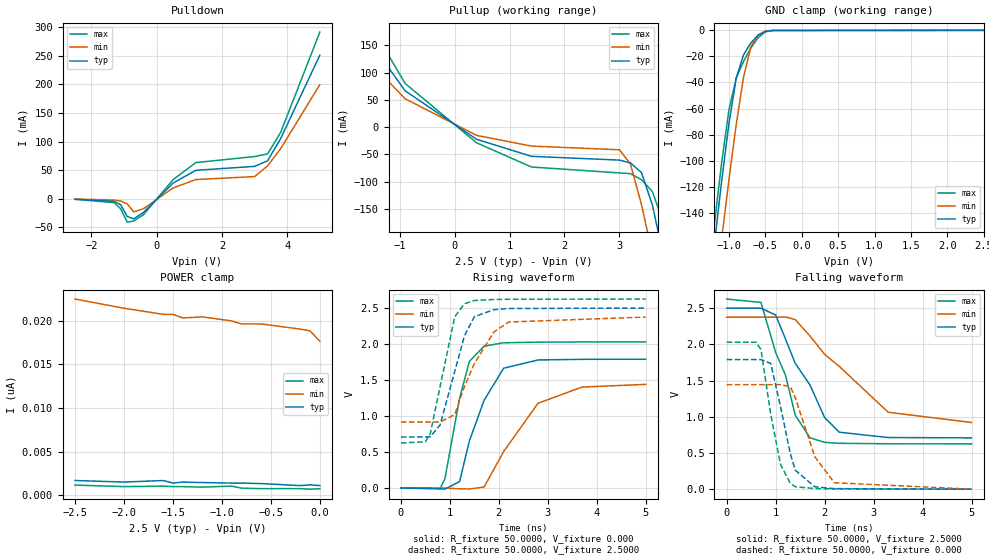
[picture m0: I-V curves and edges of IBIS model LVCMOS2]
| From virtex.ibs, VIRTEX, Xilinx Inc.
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| Note -  the values for Vref specified below refer to the IBIS
| Vref (the voltage  to which the load resistor is connected in
| the IBIS model) and not the Vref of the corresponding
| differential input standard.
| These 2 Vrefs will not necessarily have the same value for a given
| standard.
|   Model LVCMOS2
[Model]   LVCMOS2
Model_type   I/O
Polarity   Non-Inverting
Enable   Active-Low
Vinl =   0.800V
Vinh =   1.700V
Vmeas =   1.2500V
Cref =  35.0000pF
Rref =   1.0000M
Vref =  0.000V
C_comp   6.5000pF   5.0000pF   8.0000pF
[Temperature Range]   27.0000   100.0000   0.000
[Voltage Range]   2.5000V   2.3750V   2.6250V
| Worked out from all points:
|   slope of the pulldown table from 0 to 0.375 V, typ, clamps not added: 17.7 ohm
|   slope of the pullup table from 0 to 0.375 V, typ, clamps not added: 17.9 ohm
|   GND clamp passes 1 mA (typ) near -0.51 V on its own axis
|   rising waveform, R_fixture 50.0000, V_fixture 0.000: 20-80 % time 525ps typ, 808ps min, 368ps max; typ from 0 V to 1.79 V
|   rising waveform, R_fixture 50.0000, V_fixture 2.5000: 20-80 % time 456ps typ, 605ps min, 355ps max; typ from 0.708 V to 2.5 V
|   falling waveform, R_fixture 50.0000, V_fixture 2.5000: 20-80 % time 769ps typ, 1.22ns min, 524ps max; typ from 2.5 V to 0.709 V
|   falling waveform, R_fixture 50.0000, V_fixture 0.000: 20-80 % time 338ps typ, 465ps min, 296ps max; typ from 1.79 V to 0.001 V
[Pulldown]
| voltage   I(typ)   I(min)   I(max)
-2.5V     -900uA     -600uA     -1.1mA
-1.3V     -4.8mA     -2.4mA     -6.9mA
-1.1V     -10.5mA    -4mA       -17.7mA
-900mV    -31.17mA   -9.17mA    -41.13mA
-700mV    -35.25mA   -23.08mA   -39.09mA
-400mV    -23.96mA   -17.41mA   -27.92mA
500mV     27.16mA    18.74mA    33.11mA
1.2V      49.71mA    33.52mA    63.24mA
3V        56.55mA    38.7mA     73.81mA
3.4V      66.37mA    57.4mA     78.39mA
3.8V      105.3mA    87.69mA    116.1mA
5V        251.3mA    199.7mA    291.7mA
[Pullup]
| voltage   I(typ)   I(min)   I(max)
-2.5V     294mA      224.6mA    353.6mA
-1.9V     207.9mA    157.1mA    251.6mA
-900mV    66.61mA    52.06mA    80.14mA
400mV     -22.23mA   -15.11mA   -28.69mA
1.4V      -53.52mA   -34.76mA   -73.1mA
3V        -60.44mA   -41.5mA    -83.95mA
3.2V      -65.62mA   -67.47mA   -85.26mA
3.4V      -83.06mA   -141.8mA   -96.26mA
3.6V      -142.9mA   -233.3mA   -118.3mA
3.8V      -236.6mA   -330.2mA   -175.6mA
4V        -338.4mA   -429.6mA   -269.9mA
5V        -873.3mA   -939.1mA   -808.1mA
[GND_clamp]
| voltage   I(typ)   I(min)   I(max)
-2.5V     -852.1mA   -861.3mA   -847.6mA
-1.2V     -163.3mA   -206.7mA   -148.3mA
-1.1V     -115.2mA   -159.6mA   -101mA
-1V       -71.03mA   -114.2mA   -60.76mA
-900mV    -36.42mA   -71.86mA   -36.51mA
-800mV    -18.71mA   -35.86mA   -23.83mA
-700mV    -9.708mA   -12.62mA   -13.62mA
-600mV    -3.604mA   -3.647mA   -5.596mA
-500mV    -691.4uA   -852.9uA   -1.154mA
-400mV    -68.33uA   -138.4uA   -98.29uA
2.5V      1.106nA    18.89nA    640.3pA
[POWER_clamp]
| voltage   I(typ)   I(min)   I(max)
-2.5V     1.688nA    22.47nA    1.164nA
-2V       1.513nA    21.42nA    989.5pA
-1.6V     1.688nA    20.72nA    1.048nA
-1.5V     1.397nA    20.72nA    989.5pA
-1.4V     1.513nA    20.31nA    989.5pA
-1.2V     1.455nA    20.43nA    931.3pA
-900mV    1.397nA    19.97nA    1.048nA
-800mV    1.397nA    19.62nA    814.9pA
-600mV    1.339nA    19.62nA    756.7pA
-200mV    1.106nA    19.03nA    756.7pA
-100mV    1.193nA    18.83nA    698.5pA
0V        1.106nA    17.64nA    756.7pA
[Ramp]
| variable   typ   min   max
dV/dt_r   1.0734/0.5165n   0.8634/0.8467n   1.2168/0.3654n
dV/dt_f   1.0747/0.7636n   0.8722/1.2350n   1.1995/0.5417n
R_load = 50.0000
[Rising Waveform]
R_fixture = 50.0000
V_fixture = 0.000
| time   V(typ)   V(min)   V(max)
0s        0V         0V         0V
800ps     -9.391mV   985.2uV    -9.609mV
900ps     -16.16mV   -508.6uV   129mV
1.2ns     90.21mV    -11.45mV   1.248V
1.4ns     654.3mV    -13.55mV   1.758V
1.7ns     1.218V     13.46mV    1.97V
2.1ns     1.664V     506.1mV    2.017V
2.8ns     1.778V     1.176V     2.026V
3.7ns     1.787V     1.402V     2.028V
5ns       1.789V     1.439V     2.028V
[Rising Waveform]
R_fixture = 50.0000
V_fixture = 2.5000
V_fixture_min = 2.3750
V_fixture_max = 2.6250
| time   V(typ)   V(min)   V(max)
0s        707.9mV    916.3mV    625.2mV
500ps     709.4mV    916.8mV    641.9mV
600ps     712mV      916.9mV    751.8mV
800ps     874.3mV    917mV      1.404V
1.1ns     1.617V     1.019V     2.377V
1.3ns     2.115V     1.413V     2.559V
1.5ns     2.378V     1.726V     2.604V
1.9ns     2.477V     2.167V     2.618V
2.2ns     2.493V     2.305V     2.621V
5ns       2.499V     2.374V     2.624V
[Falling Waveform]
R_fixture = 50.0000
V_fixture = 2.5000
V_fixture_min = 2.3750
V_fixture_max = 2.6250
| time   V(typ)   V(min)   V(max)
0s        2.5V       2.375V     2.625V
700ps     2.499V     2.375V     2.579V
1ns       2.405V     2.374V     1.888V
1.2ns     2.076V     2.378V     1.575V
1.4ns     1.737V     2.342V     1.023V
1.7ns     1.441V     2.116V     710.4mV
2ns       988.8mV    1.862V     646.4mV
2.3ns     786.7mV    1.695V     633.8mV
3.3ns     713mV      1.062V     627.1mV
5ns       708.9mV    921.3mV    625.9mV
[Falling Waveform]
R_fixture = 50.0000
V_fixture = 0.000
| time   V(typ)   V(min)   V(max)
0s        1.79V      1.443V     2.029V
600ps     1.79V      1.443V     2.029V
700ps     1.789V     1.443V     1.929V
900ps     1.736V     1.443V     1.032V
1.1ns     1.139V     1.444V     341mV
1.3ns     488.8mV    1.415V     79.11mV
1.4ns     262.1mV    1.266V     34.67mV
1.8ns     33.78mV    447.6mV    9.057mV
2.2ns     7.545mV    89.26mV    3.999mV
5ns       519.6uV    683.1uV    467.8uV
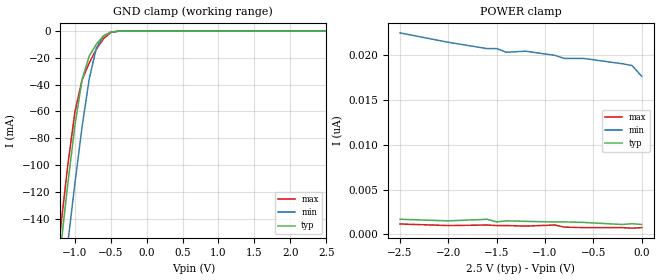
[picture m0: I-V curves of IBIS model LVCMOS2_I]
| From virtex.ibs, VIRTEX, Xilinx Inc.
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|   Model LVCMOS2_I
[Model]   LVCMOS2_I
Model_type   Input
Polarity   Non-Inverting
Vinl =   0.800V
Vinh =   1.700V
C_comp   6.5000pF   5.0000pF   8.0000pF
[Temperature Range]   27.0000   100.0000   0.000
[Voltage Range]   2.5000V   2.3750V   2.6250V
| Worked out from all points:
|   GND clamp passes 1 mA (typ) near -0.51 V on its own axis
[GND_clamp]
| voltage   I(typ)   I(min)   I(max)
-2.5V     -852.1mA   -861.3mA   -847.6mA
-1.2V     -163.3mA   -206.7mA   -148.3mA
-1.1V     -115.2mA   -159.6mA   -101mA
-1V       -71.03mA   -114.2mA   -60.76mA
-900mV    -36.42mA   -71.86mA   -36.51mA
-800mV    -18.71mA   -35.86mA   -23.83mA
-700mV    -9.708mA   -12.62mA   -13.62mA
-600mV    -3.604mA   -3.647mA   -5.596mA
-500mV    -691.4uA   -852.9uA   -1.154mA
-400mV    -68.33uA   -138.4uA   -98.29uA
2.5V      1.106nA    18.89nA    640.3pA
[POWER_clamp]
| voltage   I(typ)   I(min)   I(max)
-2.5V     1.688nA    22.47nA    1.164nA
-2V       1.513nA    21.42nA    989.5pA
-1.6V     1.688nA    20.72nA    1.048nA
-1.5V     1.397nA    20.72nA    989.5pA
-1.4V     1.513nA    20.31nA    989.5pA
-1.2V     1.455nA    20.43nA    931.3pA
-900mV    1.397nA    19.97nA    1.048nA
-800mV    1.397nA    19.62nA    814.9pA
-600mV    1.339nA    19.62nA    756.7pA
-200mV    1.106nA    19.03nA    756.7pA
-100mV    1.193nA    18.83nA    698.5pA
0V        1.106nA    17.64nA    756.7pA
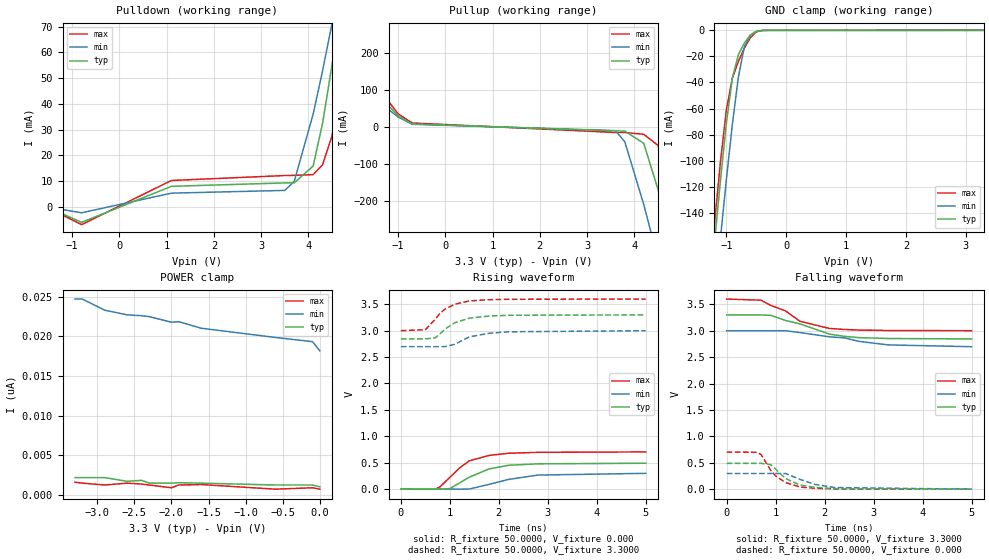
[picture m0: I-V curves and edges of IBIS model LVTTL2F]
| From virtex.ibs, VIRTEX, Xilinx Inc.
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|   Model LVTTL2F
[Model]   LVTTL2F
Model_type   I/O
Polarity   Non-Inverting
Enable   Active-Low
Vinl =   0.800V
Vinh =   2.000V
Vmeas =   1.4000V
Cref =  35.0000pF
Rref =   1.0000M
Vref =  0.000V
C_comp   6.5000pF   5.0000pF   8.0000pF
[Temperature Range]   27.0000   100.0000   0.000
[Voltage Range]   3.3000V   3.0000V   3.6000V
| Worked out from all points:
|   slope of the pulldown table from 0 to 0.495 V, typ, clamps not added: 106 ohm
|   slope of the pullup table from 0 to 0.495 V, typ, clamps not added: 139 ohm
|   GND clamp passes 1 mA (typ) near -0.51 V on its own axis
|   rising waveform, R_fixture 50.0000, V_fixture 0.000: 20-80 % time 680ps typ, 873ps min, 566ps max; typ from 0 V to 0.488 V
|   rising waveform, R_fixture 50.0000, V_fixture 3.3000: 20-80 % time 482ps typ, 579ps min, 433ps max; typ from 2.85 V to 3.3 V
|   falling waveform, R_fixture 50.0000, V_fixture 3.3000: 20-80 % time 944ps typ, 1.34ns min, 781ps max; typ from 3.3 V to 2.85 V
|   falling waveform, R_fixture 50.0000, V_fixture 0.000: 20-80 % time 435ps typ, 571ps min, 409ps max; typ from 0.489 V to 0 V
[Pulldown]
| voltage   I(typ)   I(min)   I(max)
-3.3V     0A         0A         0A
-1.5V     -400uA     -200uA     -500uA
-800mV    -6.06mA    -2.34mA    -6.94mA
1.1V      7.946mA    5.295mA    10.21mA
3.5V      9.269mA    6.357mA    12.14mA
3.7V      9.327mA    9.93mA     12.21mA
4.1V      15.87mA    36.07mA    12.5mA
4.3V      32.58mA    52.96mA    16.38mA
4.5V      55.25mA    71.28mA    27.63mA
4.7V      80.31mA    90.68mA    52.84mA
4.9V      106.7mA    110.9mA    83.48mA
6.6V      338.9mA    288.8mA    364.9mA
[Pullup]
| voltage   I(typ)   I(min)   I(max)
-3.3V     342.7mA    262.9mA    416.4mA
-2.7V     262.1mA    199.6mA    318.5mA
-1V       30.69mA    27.37mA    35.9mA
-700mV    8.534mA    7.753mA    11.26mA
3.6V      -10.07mA   -9.493mA   -14.48mA
3.8V      -10.68mA   -39.78mA   -14.57mA
4.2V      -43.78mA   -209.1mA   -19.4mA
4.5V      -167.4mA   -355.7mA   -49.03mA
4.9V      -372.8mA   -557mA     -204.3mA
5.1V      -478.9mA   -658.7mA   -308.3mA
5.3V      -585.9mA   -760.9mA   -415.3mA
6.6V      -1.29A     -1.43A     -1.128A
[GND_clamp]
| voltage   I(typ)   I(min)   I(max)
-3.3V     -1.286A    -1.273A    -1.289A
-1.2V     -163.3mA   -206.7mA   -148.3mA
-1.1V     -115.2mA   -159.6mA   -101mA
-1V       -71.04mA   -114.2mA   -60.78mA
-900mV    -36.42mA   -71.86mA   -36.53mA
-800mV    -18.72mA   -35.86mA   -23.84mA
-700mV    -9.715mA   -12.62mA   -13.63mA
-600mV    -3.608mA   -3.649mA   -5.601mA
-500mV    -692.7uA   -854.2uA   -1.156mA
-400mV    -68.48uA   -138.7uA   -98.51uA
-300mV    -4.365uA   -16.75uA   -4.597uA
3.3V      1.106nA    64.38nA    640.3pA
[POWER_clamp]
| voltage   I(typ)   I(min)   I(max)
-3.3V     2.212nA    24.68nA    1.63nA
-3.2V     2.212nA    24.68nA    1.513nA
-2.9V     2.212nA    23.28nA    1.281nA
-2.6V     1.746nA    22.7nA     1.513nA
-2.4V     1.863nA    22.58nA    1.397nA
-2.3V     1.513nA    22.47nA    1.281nA
-2V       1.513nA    21.77nA    931.3pA
-1.9V     1.572nA    21.83nA    1.281nA
-1.6V     1.513nA    21.01nA    1.339nA
-600mV    1.281nA    19.85nA    756.7pA
-100mV    1.281nA    19.32nA    931.3pA
0V        1.048nA    18.16nA    756.7pA
[Ramp]
| variable   typ   min   max
dV/dt_r   0.2928/0.6790n   0.1780/0.8698n   0.4214/0.5885n
dV/dt_f   0.2730/0.9706n   0.1812/1.3416n   0.3594/0.7762n
R_load = 50.0000
[Rising Waveform]
R_fixture = 50.0000
V_fixture = 0.000
| time   V(typ)   V(min)   V(max)
0s        0V         0V         0V
700ps     -1.402mV   158.7uV    -3.557mV
800ps     -3.332mV   127.8uV    41.13mV
1ns       7.037mV    -1.117mV   219.5mV
1.2ns     115.9mV    -3.264mV   399.8mV
1.4ns     224.8mV    -659uV     534.5mV
1.8ns     379.3mV    86.9mV     635.4mV
2.2ns     448.9mV    181.4mV    677.1mV
2.8ns     476.5mV    263.7mV    694.3mV
5ns       488mV      296.6mV    702.3mV
[Rising Waveform]
R_fixture = 50.0000
V_fixture = 3.3000
V_fixture_min = 3.0000
V_fixture_max = 3.6000
| time   V(typ)   V(min)   V(max)
0s        2.845V     2.697V     3.001V
500ps     2.845V     2.697V     3.018V
700ps     2.863V     2.697V     3.213V
800ps     2.938V     2.697V     3.33V
900ps     3.029V     2.698V     3.408V
1.1ns     3.15V      2.741V     3.5V
1.4ns     3.238V     2.883V     3.564V
1.8ns     3.277V     2.95V      3.587V
2.2ns     3.292V     2.979V     3.595V
5ns       3.299V     2.999V     3.599V
[Falling Waveform]
R_fixture = 50.0000
V_fixture = 3.3000
V_fixture_min = 3.0000
V_fixture_max = 3.6000
| time   V(typ)   V(min)   V(max)
0s        3.3V       3V         3.6V
700ps     3.299V     3V         3.579V
900ps     3.292V     3V         3.48V
1.2ns     3.195V     3.001V     3.376V
1.5ns     3.129V     2.965V     3.178V
2.1ns     2.936V     2.885V     3.043V
2.4ns     2.894V     2.866V     3.024V
2.7ns     2.87V      2.799V     3.013V
3.3ns     2.853V     2.732V     3.005V
5ns       2.845V     2.698V     3.001V
[Falling Waveform]
R_fixture = 50.0000
V_fixture = 0.000
| time   V(typ)   V(min)   V(max)
0s        488.8mV    297.5mV    703.2mV
600ps     488.9mV    297.5mV    698.7mV
700ps     489.1mV    297.5mV    658mV
900ps     463.5mV    297.5mV    355.3mV
1ns       379.6mV    297.6mV    250.5mV
1.2ns     202.4mV    296.9mV    127.5mV
1.5ns     77.9mV     184.9mV    39.96mV
1.8ns     34.46mV    89.94mV    17.67mV
2.2ns     10.29mV    31.14mV    6.439mV
5ns       380uV      326.4uV    471.7uV
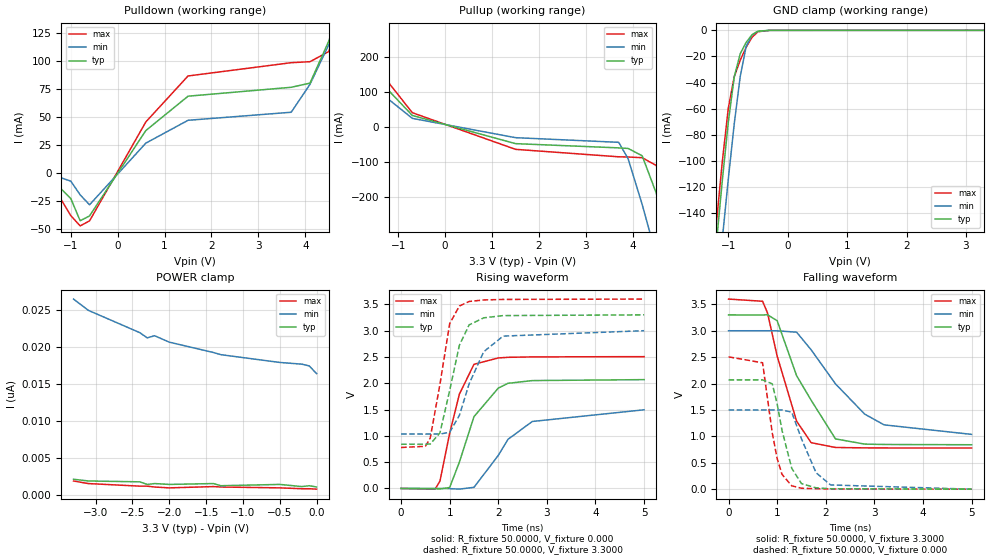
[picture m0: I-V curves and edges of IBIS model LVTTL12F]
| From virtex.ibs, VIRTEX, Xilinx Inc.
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|   Model LVTTL12F
[Model]   LVTTL12F
Model_type   I/O
Polarity   Non-Inverting
Enable   Active-Low
Vinl =   0.800V
Vinh =   2.000V
Vmeas =   1.4000V
Cref =  35.0000pF
Rref =   1.0000M
Vref =  0.000V
C_comp   6.5000pF   5.0000pF   8.0000pF
[Temperature Range]   27.0000   100.0000   0.000
[Voltage Range]   3.3000V   3.0000V   3.6000V
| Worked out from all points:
|   slope of the pulldown table from 0 to 0.495 V, typ, clamps not added: 15.4 ohm
|   slope of the pullup table from 0 to 0.495 V, typ, clamps not added: 25.2 ohm
|   GND clamp passes 1 mA (typ) near -0.51 V on its own axis
|   rising waveform, R_fixture 50.0000, V_fixture 0.000: 20-80 % time 556ps typ, 797ps min, 400ps max; typ from 0 V to 2.07 V
|   rising waveform, R_fixture 50.0000, V_fixture 3.3000: 20-80 % time 372ps typ, 492ps min, 288ps max; typ from 0.84 V to 3.3 V
|   falling waveform, R_fixture 50.0000, V_fixture 3.3000: 20-80 % time 727ps typ, 1.07ns min, 508ps max; typ from 3.3 V to 0.841 V
|   falling waveform, R_fixture 50.0000, V_fixture 0.000: 20-80 % time 305ps typ, 397ps min, 266ps max; typ from 2.07 V to 0 V
[Pulldown]
| voltage   I(typ)   I(min)   I(max)
-3.3V     4mA        3mA        6mA
-1.5V     -2mA       -300uA     -3.4mA
-1V       -22.93mA   -7.4mA     -38.21mA
-800mV    -42.8mA    -19.66mA   -47.4mA
-600mV    -38.47mA   -28.54mA   -42.9mA
600mV     37.76mA    26.53mA    45.45mA
1.5V      68.44mA    46.92mA    86.51mA
3.7V      76.41mA    54.11mA    98.37mA
4.1V      80.11mA    79.08mA    99.25mA
4.5V      117.6mA    114.4mA    108.3mA
4.7V      142.5mA    133.7mA    132.4mA
6.6V      399mA      330.4mA    441.4mA
[Pullup]
| voltage   I(typ)   I(min)   I(max)
-3.3V     401.3mA    308.2mA    484mA
-2.9V     344.8mA    263.9mA    415.5mA
-2.5V     286.5mA    217.5mA    345.7mA
-700mV    33.24mA    24.98mA    41.08mA
1.5V      -47.01mA   -30.01mA   -63.27mA
3.7V      -59.11mA   -43.28mA   -84.54mA
3.9V      -60.68mA   -90.11mA   -85.1mA
4.2V      -81.62mA   -220.4mA   -87.14mA
4.5V      -188mA     -366.4mA   -109.3mA
4.9V      -390.3mA   -567.4mA   -234.7mA
5.1V      -496.1mA   -669.1mA   -335.2mA
6.6V      -1.307A    -1.441A    -1.153A
[GND_clamp]
| voltage   I(typ)   I(min)   I(max)
-3.3V     -1.286A    -1.273A    -1.29A
-1.3V     -213.2mA   -255.1mA   -198mA
-1.2V     -163mA     -206.8mA   -147.7mA
-1.1V     -114.8mA   -159.6mA   -100.3mA
-1V       -70.57mA   -114.1mA   -59.86mA
-900mV    -35.79mA   -71.75mA   -35.46mA
-800mV    -18.04mA   -35.69mA   -22.98mA
-700mV    -9.256mA   -12.38mA   -13.06mA
-600mV    -3.388mA   -3.468mA   -5.299mA
-500mV    -637.4uA   -792.4uA   -1.07mA
-300mV    -3.973uA   -15.32uA   -4.185uA
3.3V      1.106nA    17.64nA    698.5pA
[POWER_clamp]
| voltage   I(typ)   I(min)   I(max)
-3.3V     2.095nA    26.43nA    1.863nA
-3.1V     1.863nA    24.91nA    1.513nA
-2.4V     1.746nA    21.89nA    1.164nA
-2.3V     1.397nA    21.19nA    1.164nA
-2.2V     1.513nA    21.48nA    1.048nA
-2V       1.397nA    20.61nA    931.3pA
-1.4V     1.513nA    19.21nA    1.106nA
-1.3V     1.222nA    18.92nA    1.048nA
-500mV    1.397nA    17.87nA    931.3pA
-200mV    1.106nA    17.64nA    814.9pA
-100mV    1.222nA    17.4nA     814.9pA
0V        1.048nA    16.36nA    756.7pA
[Ramp]
| variable   typ   min   max
dV/dt_r   1.2408/0.5535n   0.8970/0.7922n   1.5030/0.3954n
dV/dt_f   1.4752/0.7257n   1.1772/1.1183n   1.6925/0.5243n
R_load = 50.0000
[Rising Waveform]
R_fixture = 50.0000
V_fixture = 0.000
| time   V(typ)   V(min)   V(max)
0s        0V         0V         0V
700ps     -3.771mV   692.4uV    -13.4mV
800ps     -9.635mV   799.2uV    138.3mV
1ns       17.96mV    -3.585mV   1.048V
1.2ns     500.5mV    -12.31mV   1.792V
1.5ns     1.364V     21.02mV    2.359V
2ns       1.907V     627.7mV    2.48V
2.2ns     1.998V     933.5mV    2.492V
2.7ns     2.05V      1.273V     2.5V
5ns       2.068V     1.495V     2.505V
[Rising Waveform]
R_fixture = 50.0000
V_fixture = 3.3000
V_fixture_min = 3.0000
V_fixture_max = 3.6000
| time   V(typ)   V(min)   V(max)
0s        840.3mV    1.034V     778.4mV
500ps     841.4mV    1.034V     801.3mV
600ps     844.4mV    1.034V     955.5mV
800ps     1.055V     1.034V     1.98V
1ns       1.861V     1.067V     3.131V
1.2ns     2.721V     1.388V     3.467V
1.4ns     3.108V     1.987V     3.553V
1.7ns     3.242V     2.598V     3.582V
2.1ns     3.285V     2.895V     3.592V
5ns       3.299V     2.998V     3.599V
[Falling Waveform]
R_fixture = 50.0000
V_fixture = 3.3000
V_fixture_min = 3.0000
V_fixture_max = 3.6000
| time   V(typ)   V(min)   V(max)
0s        3.3V       3V         3.6V
700ps     3.299V     3V         3.558V
800ps     3.303V     3V         3.341V
1ns       3.19V      2.999V     2.521V
1.4ns     2.149V     2.973V     1.288V
1.7ns     1.683V     2.638V     880.4mV
2.2ns     952.2mV    1.994V     789.8mV
2.8ns     853.7mV    1.422V     782.3mV
3.2ns     846.6mV    1.218V     780.9mV
5ns       841.4mV    1.038V     779.2mV
[Falling Waveform]
R_fixture = 50.0000
V_fixture = 0.000
| time   V(typ)   V(min)   V(max)
0s        2.07V      1.5V       2.506V
700ps     2.07V      1.5V       2.393V
900ps     1.994V     1.5V       1.06V
1ns       1.615V     1.5V       581mV
1.1ns     1.113V     1.501V     280.2mV
1.3ns     395.3mV    1.458V     63.91mV
1.5ns     105.3mV    953.5mV    17.9mV
1.8ns     26.06mV    311.6mV    8.619mV
2.1ns     8.631mV    80.09mV    4.709mV
5ns       466uV      547.1uV    485uV
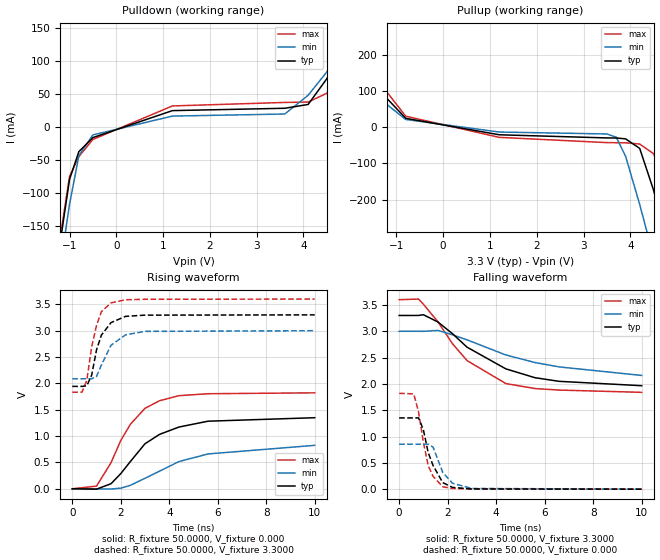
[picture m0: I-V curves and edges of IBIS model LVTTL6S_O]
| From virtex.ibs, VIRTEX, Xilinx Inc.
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|   Model LVTTL6S_O
[Model]   LVTTL6S_O
Model_type   Output
Polarity   Non-Inverting
Vmeas =   1.4000V
Cref =  35.0000pF
Rref =   1.0000M
Vref =  0.000V
C_comp   6.5000pF   5.0000pF   8.0000pF
[Temperature Range]   27.0000   100.0000   0.000
[Voltage Range]   3.3000V   3.0000V   3.6000V
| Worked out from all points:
|   slope of the pulldown table from 0 to 0.495 V, typ, clamps not added: 35.8 ohm
|   slope of the pullup table from 0 to 0.495 V, typ, clamps not added: 48 ohm
|   rising waveform, R_fixture 50.0000, V_fixture 0.000: 20-80 % time 1.86ns typ, 2.73ns min, 1.36ns max; typ from 0 V to 1.35 V
|   rising waveform, R_fixture 50.0000, V_fixture 3.3000: 20-80 % time 555ps typ, 669ps min, 473ps max; typ from 1.94 V to 3.3 V
|   falling waveform, R_fixture 50.0000, V_fixture 3.3000: 20-80 % time 2.82ns typ, 3.7ns min, 2.11ns max; typ from 3.3 V to 1.97 V
|   falling waveform, R_fixture 50.0000, V_fixture 0.000: 20-80 % time 548ps typ, 557ps min, 475ps max; typ from 1.35 V to 0 V
[Pulldown]
| voltage   I(typ)   I(min)   I(max)
-3.3V     -1.286A    -1.273A    -1.29A
-1.5V     -318.1mA   -354.4mA   -304.8mA
-1V       -79.02mA   -116.9mA   -74.9mA
-800mV    -37.01mA   -43.14mA   -44.54mA
-500mV    -15.77mA   -11.73mA   -18.61mA
1.2V      24.98mA    16.71mA    32.05mA
3.6V      28.53mA    19.84mA    37.34mA
4.1V      34.3mA     48.19mA    37.92mA
4.5V      73.34mA    83.53mA    51.22mA
5.1V      152.1mA    144.1mA    139.5mA
5.3V      179.8mA    165.4mA    172.7mA
6.6V      356.8mA    300.9mA    388.1mA
[Pullup]
| voltage   I(typ)   I(min)   I(max)
-3.3V     367mA      281.8mA    444.6mA
-2.7V     284.5mA    216.8mA    344.6mA
-800mV    24.26mA    21.1mA     30.17mA
1.2V      -21.09mA   -13.54mA   -28.27mA
3.5V      -29.77mA   -18.84mA   -42.7mA
3.7V      -29.99mA   -27.95mA   -43mA
3.9V      -32.42mA   -80.94mA   -43.28mA
4.2V      -58.74mA   -213.5mA   -46.66mA
4.5V      -175.5mA   -359.9mA   -73.69mA
4.9V      -379.7mA   -561mA     -216mA
5.1V      -485.7mA   -662.7mA   -318.8mA
6.6V      -1.296A    -1.434A    -1.138A
[Ramp]
| variable   typ   min   max
dV/dt_r   0.8088/1.8547n   0.4942/2.7770n   1.0920/1.4021n
dV/dt_f   0.8004/2.8245n   0.5034/3.6522n   1.0560/2.1117n
R_load = 50.0000
[Rising Waveform]
R_fixture = 50.0000
V_fixture = 0.000
| time   V(typ)   V(min)   V(max)
0s        0V         0V         0V
1ns       -7.73mV    -2.67mV    50.07mV
1.6ns     96.38mV    -4.985mV   496.3mV
2ns       287.3mV    11.34mV    915.6mV
2.4ns     518.9mV    66.08mV    1.225V
3ns       854.4mV    199.4mV    1.527V
3.6ns     1.032V     333.8mV    1.67V
4.4ns     1.171V     516.2mV    1.766V
5.6ns     1.282V     660.8mV    1.803V
10ns      1.348V     823.7mV    1.82V
[Rising Waveform]
R_fixture = 50.0000
V_fixture = 3.3000
V_fixture_min = 3.0000
V_fixture_max = 3.6000
| time   V(typ)   V(min)   V(max)
0s        1.942V     2.086V     1.832V
400ps     1.942V     2.086V     1.832V
600ps     1.954V     2.086V     2.059V
800ps     2.156V     2.086V     2.691V
1ns       2.634V     2.13V      3.098V
1.2ns     2.915V     2.347V     3.36V
1.6ns     3.153V     2.724V     3.527V
2.2ns     3.271V     2.921V     3.586V
3ns       3.294V     2.986V     3.595V
10ns      3.299V     2.999V     3.599V
[Falling Waveform]
R_fixture = 50.0000
V_fixture = 3.3000
V_fixture_min = 3.0000
V_fixture_max = 3.6000
| time   V(typ)   V(min)   V(max)
0s        3.3V       3V         3.6V
800ps     3.301V     3V         3.612V
1ns       3.314V     2.999V     3.514V
1.6ns     3.176V     3.016V     3.179V
2.2ns     2.954V     2.933V     2.764V
2.8ns     2.698V     2.837V     2.443V
4.4ns     2.286V     2.55V      2.007V
5.6ns     2.118V     2.406V     1.912V
6.6ns     2.049V     2.323V     1.883V
10ns      1.966V     2.161V     1.84V
[Falling Waveform]
R_fixture = 50.0000
V_fixture = 0.000
| time   V(typ)   V(min)   V(max)
0s        1.354V     854.4mV    1.821V
600ps     1.354V     854.4mV    1.811V
800ps     1.355V     854.5mV    1.468V
1ns       1.127V     854.8mV    890.2mV
1.2ns     691.3mV    855.4mV    444.2mV
1.4ns     449mV      797.3mV    242.7mV
1.8ns     124.6mV    316.7mV    45.62mV
2.2ns     33.59mV    112.4mV    13.27mV
3ns       4.913mV    13.94mV    3.409mV
10ns      385.4uV    416.8uV    370.2uV
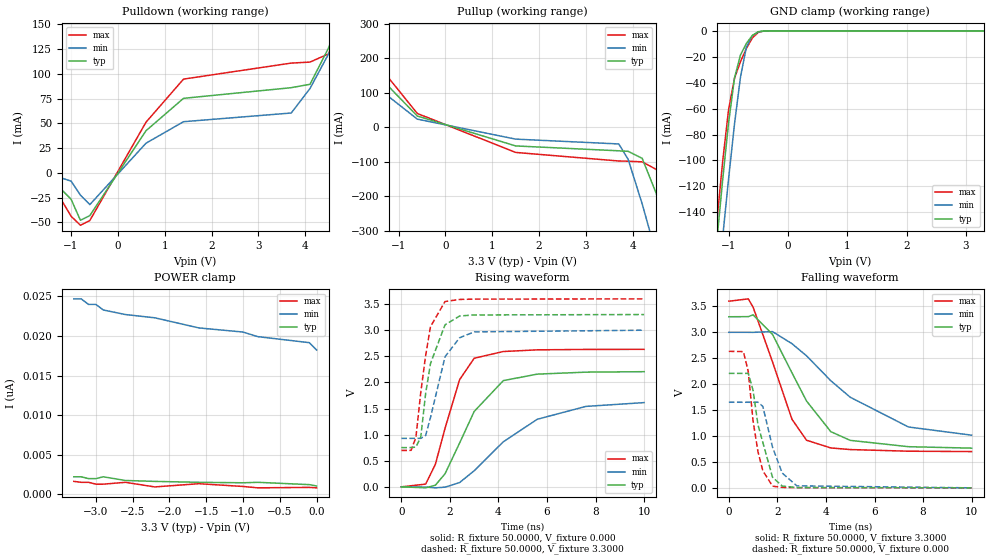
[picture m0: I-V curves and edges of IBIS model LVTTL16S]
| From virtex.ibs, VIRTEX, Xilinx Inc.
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|   Model LVTTL16S
[Model]   LVTTL16S
Model_type   I/O
Polarity   Non-Inverting
Enable   Active-Low
Vinl =   0.800V
Vinh =   2.000V
Vmeas =   1.4000V
Cref =  35.0000pF
Rref =   1.0000M
Vref =  0.000V
C_comp   6.5000pF   5.0000pF   8.0000pF
[Temperature Range]   27.0000   100.0000   0.000
[Voltage Range]   3.3000V   3.0000V   3.6000V
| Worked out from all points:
|   slope of the pulldown table from 0 to 0.495 V, typ, clamps not added: 13.7 ohm
|   slope of the pullup table from 0 to 0.495 V, typ, clamps not added: 21.7 ohm
|   GND clamp passes 1 mA (typ) near -0.51 V on its own axis
|   rising waveform, R_fixture 50.0000, V_fixture 0.000: 20-80 % time 1.49ns typ, 2.54ns min, 994ps max; typ from 0 V to 2.21 V
|   rising waveform, R_fixture 50.0000, V_fixture 3.3000: 20-80 % time 623ps typ, 703ps min, 506ps max; typ from 0.751 V to 3.3 V
|   falling waveform, R_fixture 50.0000, V_fixture 3.3000: 20-80 % time 1.82ns typ, 3.1ns min, 1.2ns max; typ from 3.3 V to 0.766 V
|   falling waveform, R_fixture 50.0000, V_fixture 0.000: 20-80 % time 590ps typ, 632ps min, 465ps max; typ from 2.21 V to 0 V
[Pulldown]
| voltage   I(typ)   I(min)   I(max)
-3.3V     4mA        3mA        5mA
-1.5V     -2.8mA     -800uA     -4.2mA
-1V       -26.72mA   -8.4mA     -43.92mA
-800mV    -48.03mA   -22.6mA    -53.04mA
-600mV    -43.31mA   -32.17mA   -48.29mA
600mV     42.55mA    29.94mA    51.16mA
1.4V      75.27mA    51.64mA    94.7mA
3.7V      86.04mA    60.44mA    110.9mA
4.1V      89.48mA    85.22mA    111.9mA
4.5V      126.6mA    120.5mA    120.3mA
4.9V      177.6mA    159.9mA    174.2mA
6.6V      407.8mA    336.3mA    452.6mA
[Pullup]
| voltage   I(typ)   I(min)   I(max)
-3.3V     413.8mA    317.9mA    498.5mA
-2.9V     356.6mA    273mA      429.3mA
-2.5V     297.6mA    226.1mA    358.6mA
-600mV    31.98mA    22.96mA    39.43mA
1.5V      -54.66mA   -34.94mA   -73.46mA
3.7V      -68.75mA   -48.9mA    -98.25mA
3.9V      -70.27mA   -93.43mA   -98.9mA
4.2V      -90.62mA   -222.7mA   -100.8mA
4.5V      -192.3mA   -368.3mA   -122.6mA
4.9V      -393.7mA   -569.2mA   -241mA
5.1V      -499.3mA   -670.9mA   -340.5mA
6.6V      -1.31A     -1.442A    -1.157A
[GND_clamp]
| voltage   I(typ)   I(min)   I(max)
-3.3V     -1.286A    -1.273A    -1.289A
-1.2V     -163.3mA   -206.7mA   -148.3mA
-1.1V     -115.2mA   -159.6mA   -101mA
-1V       -71.04mA   -114.2mA   -60.78mA
-900mV    -36.42mA   -71.86mA   -36.53mA
-800mV    -18.72mA   -35.86mA   -23.84mA
-700mV    -9.715mA   -12.62mA   -13.63mA
-600mV    -3.608mA   -3.649mA   -5.602mA
-500mV    -692.7uA   -854.2uA   -1.156mA
-400mV    -68.48uA   -138.7uA   -98.54uA
-300mV    -4.365uA   -16.73uA   -4.627uA
3.3V      1.106nA    19.44nA    40.4nA
[POWER_clamp]
| voltage   I(typ)   I(min)   I(max)
-3.3V     2.212nA    24.68nA    1.63nA
-3.2V     2.212nA    24.68nA    1.513nA
-3.1V     1.979nA    23.98nA    1.513nA
-3V       1.979nA    23.98nA    1.281nA
-2.9V     2.212nA    23.28nA    1.281nA
-2.6V     1.746nA    22.7nA     1.513nA
-2.2V     1.63nA     22.29nA    931.3pA
-1.6V     1.513nA    21.01nA    1.339nA
-1V       1.455nA    20.49nA    989.5pA
-800mV    1.513nA    19.91nA    814.9pA
-100mV    1.222nA    19.15nA    873.1pA
0V        1.048nA    18.22nA    814.9pA
[Ramp]
| variable   typ   min   max
dV/dt_r   1.3230/1.4802n   0.9678/2.6002n   1.5792/0.9791n
dV/dt_f   1.5203/1.8143n   1.1904/3.0557n   1.7401/1.1989n
R_load = 50.0000
[Rising Waveform]
R_fixture = 50.0000
V_fixture = 0.000
| time   V(typ)   V(min)   V(max)
0s        0V         0V         0V
1ns       -18.21mV   -4.471mV   51.88mV
1.4ns     30.55mV    -19.12mV   428.3mV
1.8ns     250.3mV    -5.929mV   1.121V
2.4ns     838.6mV    82.03mV    2.052V
3ns       1.443V     308.1mV    2.462V
4.2ns     2.034V     862.1mV    2.591V
5.6ns     2.158V     1.294V     2.623V
7.6ns     2.196V     1.54V      2.631V
10ns      2.205V     1.613V     2.632V
[Rising Waveform]
R_fixture = 50.0000
V_fixture = 3.3000
V_fixture_min = 3.0000
V_fixture_max = 3.6000
| time   V(typ)   V(min)   V(max)
0s        751.2mV    928.2mV    696.8mV
400ps     751.8mV    928.3mV    698.3mV
600ps     761.4mV    928.7mV    946.2mV
800ps     949.3mV    928.5mV    1.807V
1ns       1.782V     982.8mV    2.51V
1.2ns     2.361V     1.326V     3.067V
1.8ns     3.102V     2.491V     3.548V
2.4ns     3.271V     2.854V     3.588V
3ns       3.291V     2.967V     3.594V
10ns      3.299V     2.999V     3.599V
[Falling Waveform]
R_fixture = 50.0000
V_fixture = 3.3000
V_fixture_min = 3.0000
V_fixture_max = 3.6000
| time   V(typ)   V(min)   V(max)
0s        3.3V       3V         3.6V
800ps     3.302V     3V         3.645V
1ns       3.337V     2.999V     3.485V
1.8ns     2.959V     3.013V     2.428V
2.6ns     2.219V     2.781V     1.323V
3.2ns     1.675V     2.547V     918.8mV
4.2ns     1.084V     2.066V     769.7mV
5ns       916.2mV    1.748V     738.8mV
7.4ns     793.9mV    1.174V     707mV
10ns      766.2mV    1.016V     699.9mV
[Falling Waveform]
R_fixture = 50.0000
V_fixture = 0.000
| time   V(typ)   V(min)   V(max)
0s        2.208V     1.651V     2.633V
600ps     2.208V     1.651V     2.628V
800ps     2.209V     1.651V     2.242V
1ns       1.878V     1.65V      1.285V
1.2ns     1.216V     1.653V     697.4mV
1.4ns     876.5mV    1.571V     330.3mV
1.8ns     204.8mV    784mV      32.62mV
2.2ns     34.88mV    284.6mV    9.219mV
2.8ns     6.162mV    39.2mV     3.371mV
10ns      337.3uV    476.1uV    290.3uV
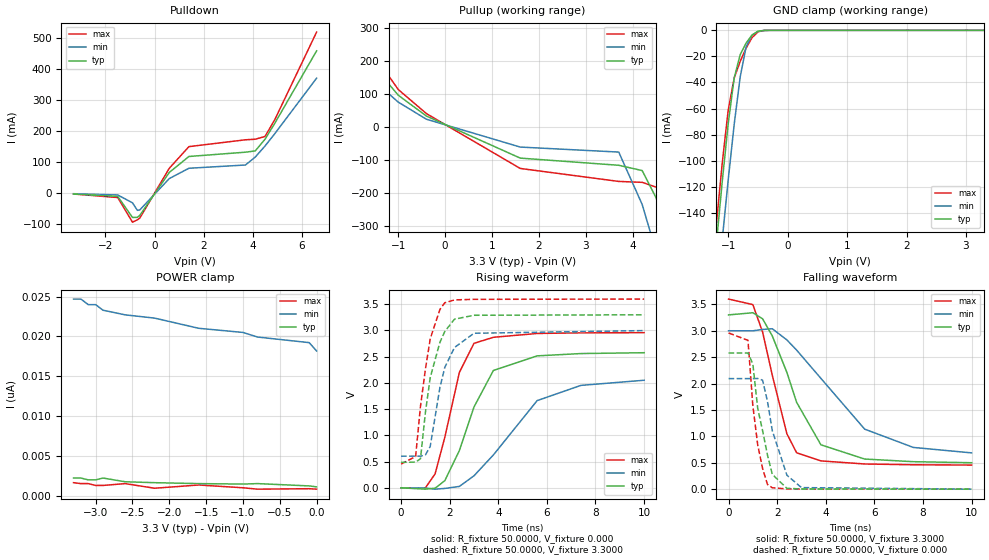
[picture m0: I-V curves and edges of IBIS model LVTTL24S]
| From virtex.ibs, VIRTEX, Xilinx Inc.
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|   Model LVTTL24S
[Model]   LVTTL24S
Model_type   I/O
Polarity   Non-Inverting
Enable   Active-Low
Vinl =   0.800V
Vinh =   2.000V
Vmeas =   1.4000V
Cref =  35.0000pF
Rref =   1.0000M
Vref =  0.000V
C_comp   6.5000pF   5.0000pF   8.0000pF
[Temperature Range]   27.0000   100.0000   0.000
[Voltage Range]   3.3000V   3.0000V   3.6000V
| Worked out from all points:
|   slope of the pulldown table from 0 to 0.495 V, typ, clamps not added: 8.65 ohm
|   slope of the pullup table from 0 to 0.495 V, typ, clamps not added: 13.4 ohm
|   GND clamp passes 1 mA (typ) near -0.51 V on its own axis
|   rising waveform, R_fixture 50.0000, V_fixture 0.000: 20-80 % time 1.29ns typ, 2.13ns min, 901ps max; typ from 0 V to 2.58 V
|   rising waveform, R_fixture 50.0000, V_fixture 3.3000: 20-80 % time 662ps typ, 689ps min, 590ps max; typ from 0.486 V to 3.3 V
|   falling waveform, R_fixture 50.0000, V_fixture 3.3000: 20-80 % time 1.47ns typ, 2.57ns min, 974ps max; typ from 3.3 V to 0.501 V
|   falling waveform, R_fixture 50.0000, V_fixture 0.000: 20-80 % time 599ps typ, 655ps min, 438ps max; typ from 2.58 V to 0 V
[Pulldown]
| voltage   I(typ)   I(min)   I(max)
-3.3V     -2mA       -1mA       -2mA
-1.5V     -9.6mA     -5.1mA     -13.4mA
-900mV    -77.58mA   -30.34mA   -92.67mA
-700mV    -77.06mA   -54.56mA   -85.09mA
-600mV    -70.64mA   -53.01mA   -79.02mA
600mV     67.49mA    47.78mA    80.85mA
1.4V      118.8mA    80.89mA    150.5mA
3.7V      132.6mA    91.36mA    172.5mA
4.1V      136.6mA    116.8mA    174.3mA
4.5V      174.4mA    152.6mA    183.2mA
4.9V      226mA      192.5mA    237.8mA
6.6V      458.7mA    370.8mA    519.1mA
[Pullup]
| voltage   I(typ)   I(min)   I(max)
-3.3V     469.9mA    361.3mA    563.1mA
-2.7V     378.5mA    289.2mA    453mA
-2.3V     314.1mA    238.4mA    376.6mA
-1V       96.63mA    75.68mA    113.8mA
-400mV    33.52mA    23.96mA    40.98mA
1.6V      -93.78mA   -60.33mA   -125.1mA
3.7V      -115.5mA   -75.52mA   -164.4mA
4.2V      -131.5mA   -234.2mA   -167.2mA
4.5V      -215mA     -378.7mA   -181.8mA
4.9V      -410.8mA   -579.2mA   -275.2mA
5.1V      -515.8mA   -680.9mA   -368.5mA
6.6V      -1.326A    -1.453A    -1.18A
[GND_clamp]
| voltage   I(typ)   I(min)   I(max)
-3.3V     -1.286A    -1.273A    -1.289A
-1.2V     -163.3mA   -206.7mA   -148.3mA
-1.1V     -115.2mA   -159.6mA   -101mA
-1V       -71.04mA   -114.2mA   -60.78mA
-900mV    -36.42mA   -71.86mA   -36.53mA
-800mV    -18.72mA   -35.86mA   -23.84mA
-700mV    -9.715mA   -12.62mA   -13.63mA
-600mV    -3.608mA   -3.649mA   -5.601mA
-500mV    -692.7uA   -854.2uA   -1.156mA
-400mV    -68.48uA   -138.7uA   -98.51uA
-300mV    -4.365uA   -16.73uA   -4.597uA
3.3V      1.164nA    19.38nA    756.7pA
[POWER_clamp]
| voltage   I(typ)   I(min)   I(max)
-3.3V     2.212nA    24.68nA    1.63nA
-3.2V     2.212nA    24.68nA    1.513nA
-3.1V     1.979nA    23.98nA    1.513nA
-3V       1.979nA    23.98nA    1.281nA
-2.9V     2.212nA    23.28nA    1.281nA
-2.6V     1.746nA    22.7nA     1.513nA
-2.2V     1.63nA     22.29nA    931.3pA
-1.6V     1.513nA    21.01nA    1.339nA
-1V       1.455nA    20.49nA    989.5pA
-800mV    1.513nA    19.91nA    814.9pA
-100mV    1.222nA    19.21nA    873.1pA
0V        1.106nA    18.16nA    814.9pA
[Ramp]
| variable   typ   min   max
dV/dt_r   1.5456/1.2746n   1.2306/2.2112n   1.7748/0.8855n
dV/dt_f   1.6795/1.4710n   1.3876/2.6117n   1.8860/0.9701n
R_load = 50.0000
[Rising Waveform]
R_fixture = 50.0000
V_fixture = 0.000
| time   V(typ)   V(min)   V(max)
0s        0V         0V         0V
1ns       -25.27mV   -3.609mV   -1.617mV
1.4ns     -7.814mV   -25.74mV   265.4mV
1.8ns     135.7mV    -11.98mV   961.8mV
2.4ns     711.3mV    26.65mV    2.201V
3ns       1.54V      228.8mV    2.755V
3.8ns     2.238V     627.6mV    2.87V
5.6ns     2.516V     1.663V     2.943V
7.4ns     2.56V      1.953V     2.955V
10ns      2.576V     2.051V     2.958V
[Rising Waveform]
R_fixture = 50.0000
V_fixture = 3.3000
V_fixture_min = 3.0000
V_fixture_max = 3.6000
| time   V(typ)   V(min)   V(max)
0s        485.6mV    602.6mV    453.2mV
600ps     489.9mV    603.2mV    596.7mV
800ps     554.7mV    603.3mV    1.556V
1ns       1.428V     625.6mV    2.254V
1.2ns     2.102V     789.2mV    2.84V
1.6ns     2.776V     1.915V     3.401V
1.8ns     2.981V     2.297V     3.529V
2.2ns     3.216V     2.676V     3.583V
3ns       3.29V      2.947V     3.594V
10ns      3.299V     2.998V     3.599V
[Falling Waveform]
R_fixture = 50.0000
V_fixture = 3.3000
V_fixture_min = 3.0000
V_fixture_max = 3.6000
| time   V(typ)   V(min)   V(max)
0s        3.3V       3V         3.6V
1ns       3.341V     2.999V     3.495V
1.4ns     3.227V     3.024V     2.977V
1.8ns     2.901V     3.038V     2.157V
2.4ns     2.211V     2.826V     1.049V
2.8ns     1.645V     2.634V     690.4mV
3.8ns     840.2mV    2.098V     535.6mV
5.6ns     570.6mV    1.137V     477.1mV
7.6ns     520.7mV    790.8mV    462.1mV
10ns      500.8mV    687.4mV    456.6mV
[Falling Waveform]
R_fixture = 50.0000
V_fixture = 0.000
| time   V(typ)   V(min)   V(max)
0s        2.579V     2.094V     2.959V
800ps     2.579V     2.094V     2.818V
1ns       2.368V     2.094V     1.575V
1.2ns     1.529V     2.096V     836.6mV
1.4ns     1.107V     2.064V     392.6mV
1.6ns     648.2mV    1.667V     90.39mV
1.8ns     280.3mV    1.107V     26.98mV
2.4ns     16.7mV     265.1mV    5.637mV
3ns       4.297mV    29.77mV    2.412mV
10ns      299.8uV    531.4uV    241uV
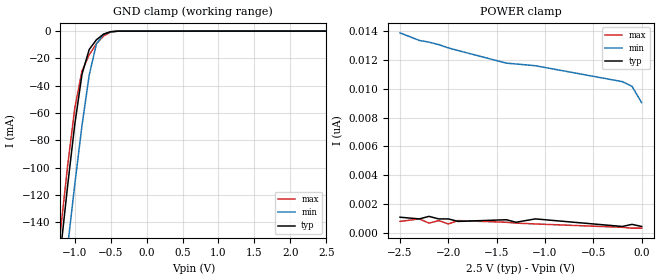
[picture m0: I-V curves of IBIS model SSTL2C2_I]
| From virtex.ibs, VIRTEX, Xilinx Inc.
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|   Model SSTL2C2_I
[Model]   SSTL2C2_I
Model_type   Input
Polarity   Non-Inverting
Vinl =   1.070V
Vinh =   1.430V
C_comp   6.5000pF   5.0000pF   8.0000pF
[Temperature Range]   27.0000   100.0000   0.000
[Voltage Range]   2.5000V   2.3750V   2.6250V
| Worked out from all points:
|   GND clamp passes 1 mA (typ) near -0.53 V on its own axis
[GND_clamp]
| voltage   I(typ)   I(min)   I(max)
-2.5V     -851.8mA   -860.9mA   -847.5mA
-1.2V     -161.8mA   -205.3mA   -146.7mA
-1.1V     -113.2mA   -157.8mA   -98.56mA
-1V       -68.04mA   -112mA     -56.27mA
-900mV    -31.6mA    -69.09mA   -29.2mA
-800mV    -13.5mA    -32.34mA   -17.42mA
-700mV    -6.408mA   -9.455mA   -9.303mA
-600mV    -2.237mA   -2.349mA   -3.538mA
-500mV    -423.5uA   -545.3uA   -698.2uA
-400mV    -42.44uA   -91.28uA   -59.93uA
2.5V      465.7pA    32.48nA    261.9pA
[POWER_clamp]
| voltage   I(typ)   I(min)   I(max)
-2.5V     1.106nA    13.85nA    814.9pA
-2.3V     989.5pA    13.33nA    989.5pA
-2.2V     1.164nA    13.21nA    698.5pA
-2.1V     989.5pA    13.04nA    873.1pA
-2V       989.5pA    12.81nA    640.3pA
-1.9V     814.9pA    12.63nA    873.1pA
-1.4V     931.3pA    11.76nA    756.7pA
-1.3V     756.7pA    11.7nA     698.5pA
-1.1V     989.5pA    11.58nA    640.3pA
-200mV    465.7pA    10.48nA    407.5pA
-100mV    611.2pA    10.16nA    349.2pA
0V        465.7pA    9.022nA    349.2pA
